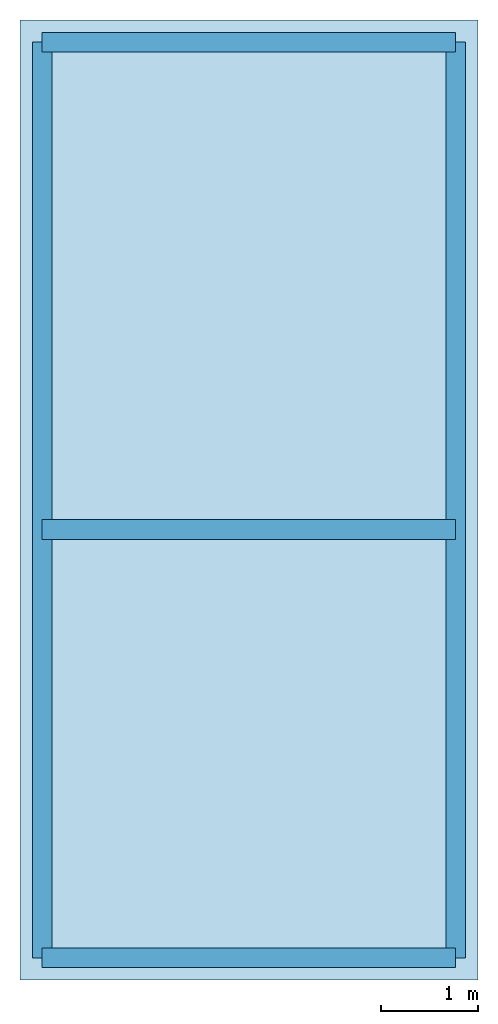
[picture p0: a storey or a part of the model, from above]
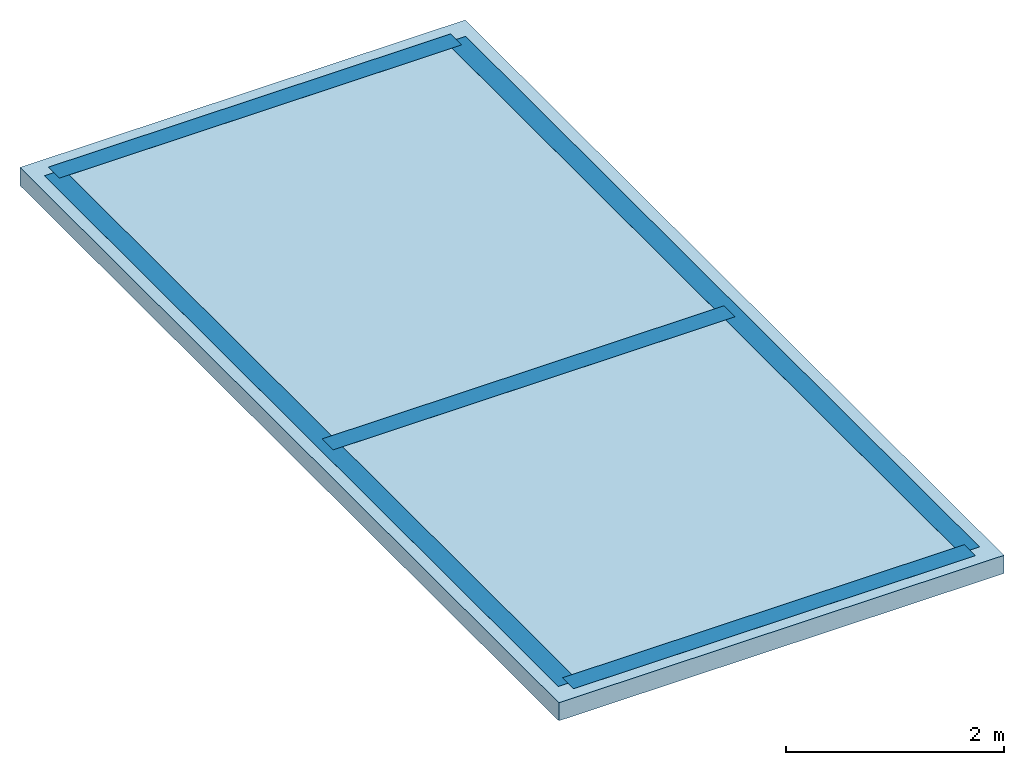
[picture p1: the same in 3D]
Properties of the parts of a building model (IFC2X3)

# File
Description: ViewDefinition [CoordinationView], Option [Visible elements;Keep GUIDs;All Domain;All elements;All struct.;scale:100.000000;CSG:Extruded;Comp. wall:Extruded;Building element parts;Chained beam:Extruded;Comp. slab:Extruded]
File name: C:\Users\Guillermo\Desktop\EJEMPLOS BIM AMAYA\Edificio viviendas\IFC\Ejemplo_StruBIM_sh.ifc
Time: 2016-02-12T08:48:24
Author: Architect
Organization: Building Designer Office
Written by: PreProc - EDM 5.0
Made in: IFC file generated by Graphisoft ArchiCAD-64 16.0.0 SPA FULL Windows version (IFC2x3 add-on version: 3270 SPA FULL).
Authorization: The authorising person

# IfcSite, Sitio
RefLatitude: 40, 25, 0, 0; RefLongitude: -3, -43, 0, 0

# IfcBuildingStorey (7)
In: Ejemplo_StruBIM
Name | Elevation (mm)
Low level | 0
First floor | 3200.4
Second floor | 6400.8
Third floor | 9601.2
Fourth floor | 12801.6
Cover | 16002
Stand | 19202.4

# IfcBeam: 12"X8" (237)
Material: Hormigón armado
AC_Pset_RenovationAndPhasing - Renovation Status: Existing
Pset_BeamCommon - LoadBearing: yes; IsExternal: no; Reference: 12"X8"
Name | In
4 x Viga-023 | First floor
4 x Viga-024 | First floor
4 x Viga-030 | First floor
5 x Viga-036 | First floor
2 x Viga-025 | First floor
2 x Viga-026 | First floor
2 x Viga-027 | First floor
2 x Viga-028 | First floor
2 x Viga-029 | First floor
2 x Viga-031 | First floor
2 x Viga-032 | First floor
5 x Viga-034 | First floor
4 x Viga-033 | First floor
3 x Viga-035 | First floor
2 x Viga-037 | First floor
2 x Viga-038 | First floor
Viga-039 | First floor
4 x Viga-028 | Second floor
2 x Viga-029 | Second floor
2 x Viga-030 | Second floor
2 x Viga-031 | Second floor
2 x Viga-032 | Second floor
2 x Viga-033 | Second floor
2 x Viga-034 | Second floor
2 x Viga-035 | Second floor
Viga-050 | Second floor
2 x Viga-037 | Second floor
2 x Viga-038 | Second floor
2 x Viga-039 | Second floor
2 x Viga-040 | Second floor
3 x Viga-041 | Second floor
3 x Viga-042 | Second floor
3 x Viga-043 | Second floor
3 x Viga-044 | Second floor
2 x Viga-045 | Second floor
2 x Viga-046 | Second floor
Viga-049 | Second floor
Viga-047 | Second floor
Viga-048 | Second floor
4 x Viga-028 | Third floor
2 x Viga-029 | Third floor
2 x Viga-030 | Third floor
2 x Viga-031 | Third floor
2 x Viga-032 | Third floor
2 x Viga-033 | Third floor
2 x Viga-034 | Third floor
2 x Viga-035 | Third floor
2 x Viga-037 | Third floor
2 x Viga-038 | Third floor
2 x Viga-039 | Third floor
3 x Viga-040 | Third floor
3 x Viga-041 | Third floor
3 x Viga-042 | Third floor
3 x Viga-043 | Third floor
2 x Viga-044 | Third floor
2 x Viga-045 | Third floor
2 x Viga-046 | Third floor
Viga-047 | Third floor
Viga-048 | Third floor
Viga-049 | Third floor
Viga-050 | Third floor
4 x Viga-028 | Fourth floor
2 x Viga-029 | Fourth floor
2 x Viga-030 | Fourth floor
2 x Viga-031 | Fourth floor
2 x Viga-032 | Fourth floor
2 x Viga-033 | Fourth floor
2 x Viga-034 | Fourth floor
2 x Viga-035 | Fourth floor
2 x Viga-037 | Fourth floor
2 x Viga-038 | Fourth floor
2 x Viga-039 | Fourth floor
3 x Viga-040 | Fourth floor
3 x Viga-041 | Fourth floor
3 x Viga-042 | Fourth floor
3 x Viga-043 | Fourth floor
2 x Viga-044 | Fourth floor
2 x Viga-045 | Fourth floor
2 x Viga-046 | Fourth floor
Viga-047 | Fourth floor
Viga-048 | Fourth floor
Viga-049 | Fourth floor
Viga-050 | Fourth floor
4 x Viga-028 | Cover
2 x Viga-029 | Cover
2 x Viga-030 | Cover
2 x Viga-031 | Cover
2 x Viga-032 | Cover
2 x Viga-033 | Cover
2 x Viga-034 | Cover
2 x Viga-035 | Cover
2 x Viga-037 | Cover
2 x Viga-038 | Cover
2 x Viga-039 | Cover
3 x Viga-040 | Cover
3 x Viga-041 | Cover
3 x Viga-042 | Cover
3 x Viga-043 | Cover
2 x Viga-044 | Cover
2 x Viga-045 | Cover
2 x Viga-046 | Cover
Viga-047 | Cover
Viga-048 | Cover
Viga-049 | Cover
Viga-050 | Cover
Viga-055 | Stand
Viga-054 | Stand
Viga-051 | Stand
Viga-052 | Stand
Viga-053 | Stand

# IfcBeam: 8"X12" (5)
Material: Hormigón armado
AC_Pset_RenovationAndPhasing - Renovation Status: Existing
Pset_BeamCommon - LoadBearing: yes; IsExternal: no; Reference: 8"X12"
Name | In
Viga-034 | First floor
Viga-036 | Second floor
Viga-036 | Third floor
Viga-036 | Fourth floor
Viga-036 | Cover

# IfcBeam: 8"X6" (5)
Material: Hormigón armado
AC_Pset_RenovationAndPhasing - Renovation Status: Existing
Pset_BeamCommon - LoadBearing: yes; IsExternal: no; Reference: 8"X6"
Name | In
Viga-035 | First floor
Viga-035 | Second floor
Viga-035 | Third floor
Viga-035 | Fourth floor
Viga-035 | Cover

# IfcColumn: 12"X12" (20)
Material: Hormigón armado
AC_Pset_RenovationAndPhasing - Renovation Status: Existing
Pset_ColumnCommon - LoadBearing: yes; IsExternal: no; Reference: 12"X12"
Name | In
P1 | Low level
P24 | Low level
P5 | Low level
P29 | Low level
P1 | First floor
P24 | First floor
P5 | First floor
P29 | First floor
P29 | Second floor
P5 | Second floor
P24 | Second floor
P1 | Second floor
P29 | Third floor
P5 | Third floor
P24 | Third floor
P1 | Third floor
P1 | Fourth floor
P24 | Fourth floor
P5 | Fourth floor
P29 | Fourth floor

# IfcColumn: 12"X14" (30)
Material: Hormigón armado
AC_Pset_RenovationAndPhasing - Renovation Status: Existing
Pset_ColumnCommon - LoadBearing: yes; IsExternal: no; Reference: 12"X14"
Name | In
P6 | Low level
P12 | Low level
P18 | Low level
P11 | Low level
P17 | Low level
P23 | Low level
2 x Pilar-004 | First floor
P12 | First floor
P18 | First floor
P17 | First floor
P23 | First floor
P23 | Second floor
P17 | Second floor
2 x Pilar-004 | Second floor
P18 | Second floor
P12 | Second floor
P23 | Third floor
P17 | Third floor
2 x Pilar-004 | Third floor
P18 | Third floor
P12 | Third floor
2 x Pilar-004 | Fourth floor
P12 | Fourth floor
P18 | Fourth floor
P17 | Fourth floor
P23 | Fourth floor

# IfcColumn: 14"X12" (35)
Material: Hormigón armado
AC_Pset_RenovationAndPhasing - Renovation Status: Existing
Pset_ColumnCommon - LoadBearing: yes; IsExternal: no; Reference: 14"X12"
Name | In
P2 | Low level
P3 | Low level
P26 | Low level
P25 | Low level
P4 | Low level
P27 | Low level
P28 | Low level
P2 | First floor
P3 | First floor
P26 | First floor
P25 | First floor
P4 | First floor
P27 | First floor
P28 | First floor
P28 | Second floor
P27 | Second floor
P4 | Second floor
P25 | Second floor
P26 | Second floor
P3 | Second floor
P2 | Second floor
P28 | Third floor
P27 | Third floor
P4 | Third floor
P25 | Third floor
P26 | Third floor
P3 | Third floor
P2 | Third floor
P2 | Fourth floor
P3 | Fourth floor
P26 | Fourth floor
P25 | Fourth floor
P4 | Fourth floor
P27 | Fourth floor
P28 | Fourth floor

# IfcColumn: 14"X14" (66)
Material: Hormigón armado
AC_Pset_RenovationAndPhasing - Renovation Status: Existing
Pset_ColumnCommon - LoadBearing: yes; IsExternal: no; Reference: 14"X14"
Name | In
P7 | Low level
P13 | Low level
P19 | Low level
P20 | Low level
P14 | Low level
P8 | Low level
P10 | Low level
P16 | Low level
P22 | Low level
P21 | Low level
P15 | Low level
P9 | Low level
4 x Pilar-004 | First floor
P13 | First floor
P19 | First floor
P20 | First floor
P14 | First floor
P16 | First floor
P22 | First floor
P21 | First floor
P15 | First floor
4 x Pilar-004 | Second floor
P15 | Second floor
P21 | Second floor
P22 | Second floor
P16 | Second floor
P14 | Second floor
P20 | Second floor
P19 | Second floor
P13 | Second floor
4 x Pilar-004 | Third floor
P15 | Third floor
P21 | Third floor
P22 | Third floor
P16 | Third floor
P14 | Third floor
P20 | Third floor
P19 | Third floor
P13 | Third floor
4 x Pilar-004 | Fourth floor
P13 | Fourth floor
P19 | Fourth floor
P20 | Fourth floor
P14 | Fourth floor
P16 | Fourth floor
P22 | Fourth floor
P21 | Fourth floor
P15 | Fourth floor
P21 | Cover
P9 | Cover
P20 | Cover
P8 | Cover
P15 | Cover
P14 | Cover

# IfcDoor: Puerta 16 (6)
Type - OperationType: SINGLE_SWING_LEFT; ParameterTakesPrecedence: no; Sizeable: no
Type - IfcDoorLiningProperties - LiningDepth: 0.115 mm; LiningThickness: 0.04 mm; ThresholdDepth: 0.01 mm; ThresholdThickness: 0.012 mm
Type - IfcDoorPanelProperties - PanelDepth: 0.04 mm; PanelOperation: SWINGING; PanelWidth: 0.844; PanelPosition: MIDDLE
OverallHeight: 2100 mm; OverallWidth: 900 mm; Material: Fondo
AC_Pset_RenovationAndPhasing - Renovation Status: Existing
Name | In
P01 | Low level
P02 | First floor
P02 | Second floor
P02 | Third floor
P02 | Fourth floor
P01 | Cover

# IfcDoor: Puerta 16 (6)
Type - OperationType: SINGLE_SWING_RIGHT; ParameterTakesPrecedence: no; Sizeable: no
Type - IfcDoorLiningProperties - LiningDepth: 0.115 mm; LiningThickness: 0.04 mm; ThresholdDepth: 0.01 mm; ThresholdThickness: 0.012 mm
Type - IfcDoorPanelProperties - PanelDepth: 0.04 mm; PanelOperation: SWINGING; PanelWidth: 0.844; PanelPosition: MIDDLE
OverallHeight: 2100 mm; OverallWidth: 900 mm; Material: Fondo
AC_Pset_RenovationAndPhasing - Renovation Status: Existing
Name | In
P01 | Low level
P01 | First floor
P01 | Second floor
P01 | Third floor
P01 | Fourth floor
P02 | Cover

# IfcDoor: Puerta Doble 16 (7)
Type - OperationType: SINGLE_SWING_LEFT; ParameterTakesPrecedence: no; Sizeable: no
Type - IfcDoorLiningProperties - LiningDepth: 0.115 mm; LiningThickness: 0.04 mm; ThresholdDepth: 0.01 mm; ThresholdThickness: 0.012 mm
Type - IfcDoorPanelProperties - PanelDepth: 0.04 mm; PanelOperation: SWINGING; PanelWidth: 1.444; PanelPosition: MIDDLE
OverallHeight: 2100 mm; OverallWidth: 1500 mm; Material: Fondo
AC_Pset_RenovationAndPhasing - Renovation Status: Existing
Name | In
P07 | First floor
P04 | Second floor
P05 | Second floor
P04 | Third floor
P05 | Third floor
P04 | Fourth floor
P05 | Fourth floor

# IfcDoor: Puerta Doble 16, P06
In: First floor
Type - OperationType: SINGLE_SWING_RIGHT; ParameterTakesPrecedence: no; Sizeable: no
Type - IfcDoorLiningProperties - LiningDepth: 0.115 mm; LiningThickness: 0.04 mm; ThresholdDepth: 0.01 mm; ThresholdThickness: 0.012 mm
Type - IfcDoorPanelProperties - PanelDepth: 0.04 mm; PanelOperation: SWINGING; PanelWidth: 1.444; PanelPosition: MIDDLE
OverallHeight: 2100 mm; OverallWidth: 1500 mm; Material: Fondo
AC_Pset_RenovationAndPhasing - Renovation Status: Existing

# IfcSlab (6)
PredefinedType: FLOOR; Material: Hormigón armado 203.2 mm
AC_Pset_RenovationAndPhasing - Renovation Status: Existing
Pset_SlabCommon - LoadBearing: yes; IsExternal: no
Name | In
Forj-003 | First floor
Forj-003 | Second floor
Forj-003 | Third floor
Forj-003 | Fourth floor
Forj-004 | Cover
Forj-005 | Stand

# IfcWallStandardCase: Bloque mampostería 11 3/4" (113)
Material: Bloque mampostería 300 mm
AC_Pset_RenovationAndPhasing - Renovation Status: Existing
Pset_WallCommon - LoadBearing: yes; IsExternal: yes
Name | In
Muro-001 | Low level
Muro-002 | Low level
Muro-003 | Low level
Muro-004 | Low level
2 x Muro-010 | First floor
Muro-006 | First floor
2 x Muro-007 | First floor
3 x Muro-008 | First floor
4 x Muro-009 | First floor
Muro-015 | First floor
2 x Muro-011 | First floor
2 x Muro-012 | First floor
Muro-013 | First floor
Muro-014 | First floor
4 x Muro-009 | Second floor
3 x Muro-008 | Second floor
Muro-016 | Second floor
Muro-006 | Second floor
2 x Muro-007 | Second floor
2 x Muro-010 | Second floor
2 x Muro-014 | Second floor
3 x Muro-015 | Second floor
2 x Muro-011 | Second floor
2 x Muro-012 | Second floor
Muro-013 | Second floor
Muro-006 | Third floor
2 x Muro-007 | Third floor
3 x Muro-008 | Third floor
4 x Muro-009 | Third floor
2 x Muro-010 | Third floor
2 x Muro-014 | Third floor
3 x Muro-015 | Third floor
2 x Muro-011 | Third floor
2 x Muro-012 | Third floor
Muro-013 | Third floor
Muro-016 | Third floor
Muro-006 | Fourth floor
2 x Muro-007 | Fourth floor
3 x Muro-008 | Fourth floor
4 x Muro-009 | Fourth floor
2 x Muro-010 | Fourth floor
2 x Muro-014 | Fourth floor
3 x Muro-015 | Fourth floor
2 x Muro-011 | Fourth floor
2 x Muro-012 | Fourth floor
Muro-013 | Fourth floor
Muro-016 | Fourth floor
2 x Muro-018 | Cover
Muro-016 | Cover
Muro-015 | Cover
Muro-035 | Cover
Muro-034 | Cover
Muro-033 | Cover
Muro-032 | Cover
Muro-031 | Cover
Muro-030 | Cover
Muro-029 | Cover
Muro-017 | Cover
Muro-027 | Cover
Muro-026 | Cover
Muro-025 | Cover
Muro-024 | Cover
Muro-023 | Cover
Muro-022 | Cover
Muro-021 | Cover
Muro-020 | Cover
Muro-019 | Cover

# IfcWallStandardCase: Bloque mampostería 19 3/4" (6)
Material: Bloque mampostería 500 mm
AC_Pset_RenovationAndPhasing - Renovation Status: Existing
Pset_WallCommon - LoadBearing: yes; IsExternal: yes
Name | In
Muro-015 | Second floor
Muro-014 | Second floor
Muro-014 | Third floor
Muro-015 | Third floor
Muro-014 | Fourth floor
Muro-015 | Fourth floor

# IfcWallStandardCase: Bloque mampostería 6" (20)
Material: Bloque mampostería 150 mm
AC_Pset_RenovationAndPhasing - Renovation Status: Existing
Pset_WallCommon - LoadBearing: yes; IsExternal: yes
Name | In
Muro-010 | First floor
Muro-011 | First floor
Muro-012 | Second floor
Muro-013 | Second floor
Muro-014 | Second floor
Muro-015 | Second floor
Muro-016 | Second floor
Muro-017 | Second floor
Muro-012 | Third floor
Muro-013 | Third floor
Muro-014 | Third floor
Muro-015 | Third floor
Muro-016 | Third floor
Muro-017 | Third floor
Muro-017 | Fourth floor
Muro-016 | Fourth floor
Muro-015 | Fourth floor
Muro-014 | Fourth floor
Muro-013 | Fourth floor
Muro-012 | Fourth floor

# IfcWindow: Ventana Doble Hoja 16 (75)
Type - OperationType: DOUBLE_PANEL_HORIZONTAL; ParameterTakesPrecedence: no; Sizeable: no
Type - IfcWindowLiningProperties - LiningDepth: 50 mm; LiningThickness: 50 mm
Type - IfcWindowPanelProperties - PanelPosition: TOP; FrameDepth: 50 mm; FrameThickness: 50 mm
OverallHeight: 1400 mm; Material: Fondo
AC_Pset_RenovationAndPhasing - Renovation Status: Existing
Name | In | OverallWidth (mm)
V06 | First floor | 1820
V07 | First floor | 1820
V05 | First floor | 1820
V16 | First floor | 1820
V17 | First floor | 1820
V20 | First floor | 1820
V21 | First floor | 1820
V03 | First floor | 1820
V04 | First floor | 1820
V10 | First floor | 1820
V08 | First floor | 1820
V09 | First floor | 1820
V11 | First floor | 1820
V12 | First floor | 1820
V13 | First floor | 1820
V14 | First floor | 1820
V15 | First floor | 1820
V05 | Second floor | 1820
V19 | Second floor | 1820
V06 | Second floor | 1820
V07 | Second floor | 1820
V01 | Second floor | 1500
V16 | Second floor | 1820
V17 | Second floor | 1820
V03 | Second floor | 1820
V04 | Second floor | 1820
V10 | Second floor | 1820
V08 | Second floor | 1820
V09 | Second floor | 1820
V11 | Second floor | 1820
V12 | Second floor | 1820
V13 | Second floor | 1820
V18 | Second floor | 1820
V14 | Second floor | 1820
V15 | Second floor | 1820
V02 | Second floor | 1500
V05 | Third floor | 1820
V19 | Third floor | 1820
V06 | Third floor | 1820
V07 | Third floor | 1820
V01 | Third floor | 1500
V16 | Third floor | 1820
V17 | Third floor | 1820
V03 | Third floor | 1820
V04 | Third floor | 1820
V10 | Third floor | 1820
V08 | Third floor | 1820
V09 | Third floor | 1820
V11 | Third floor | 1820
V12 | Third floor | 1820
V13 | Third floor | 1820
V18 | Third floor | 1820
V14 | Third floor | 1820
V15 | Third floor | 1820
V02 | Third floor | 1500
V05 | Fourth floor | 1820
V19 | Fourth floor | 1820
V06 | Fourth floor | 1820
V07 | Fourth floor | 1820
V01 | Fourth floor | 1500
V16 | Fourth floor | 1820
V17 | Fourth floor | 1820
V03 | Fourth floor | 1820
V04 | Fourth floor | 1820
V10 | Fourth floor | 1820
V08 | Fourth floor | 1820
V09 | Fourth floor | 1820
V11 | Fourth floor | 1820
V12 | Fourth floor | 1820
V13 | Fourth floor | 1820
V18 | Fourth floor | 1820
V14 | Fourth floor | 1820
V15 | Fourth floor | 1820
V02 | Fourth floor | 1500
V22 | Cover | 1820
